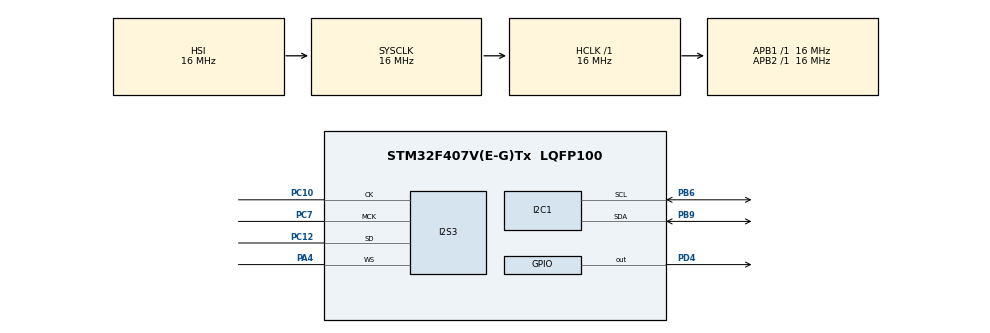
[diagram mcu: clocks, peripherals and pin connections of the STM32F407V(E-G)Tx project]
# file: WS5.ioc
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Dma.Request0=SPI3_TX
Dma.SPI3_TX.0.Direction=DMA_MEMORY_TO_PERIPH
Dma.SPI3_TX.0.FIFOMode=DMA_FIFOMODE_ENABLE
Dma.SPI3_TX.0.FIFOThreshold=DMA_FIFO_THRESHOLD_FULL
Dma.SPI3_TX.0.Instance=DMA1_Stream5
Dma.SPI3_TX.0.MemBurst=DMA_MBURST_SINGLE
Dma.SPI3_TX.0.MemDataAlignment=DMA_MDATAALIGN_HALFWORD
Dma.SPI3_TX.0.MemInc=DMA_MINC_ENABLE
Dma.SPI3_TX.0.Mode=DMA_CIRCULAR
Dma.SPI3_TX.0.PeriphBurst=DMA_PBURST_SINGLE
Dma.SPI3_TX.0.PeriphDataAlignment=DMA_PDATAALIGN_HALFWORD
Dma.SPI3_TX.0.PeriphInc=DMA_PINC_DISABLE
Dma.SPI3_TX.0.Priority=DMA_PRIORITY_LOW
I2S3.AudioFreq=I2S_AUDIOFREQ_48K
I2S3.ErrorAudioFreq=-2.34 %
I2S3.FullDuplexMode=I2S_FULLDUPLEXMODE_DISABLE
I2S3.Instance=SPI$Index
I2S3.RealAudioFreq=46.875 KHz
I2S3.VirtualMode=I2S_MODE_MASTER
Mcu.Family=STM32F4
Mcu.Name=STM32F407V(E-G)Tx
Mcu.Package=LQFP100
NVIC.DMA1_Stream5_IRQn=true\:0\:0\:false\:false\:true\:false\:true\:true
NVIC.PriorityGroup=NVIC_PRIORITYGROUP_4
PA4.Mode=Half_Duplex_Master
PA4.Signal=I2S3_WS
PB6.Mode=I2C
PB6.Signal=I2C1_SCL
PB9.Mode=I2C
PB9.Signal=I2C1_SDA
PC10.Mode=Half_Duplex_Master
PC10.Signal=I2S3_CK
PC12.Mode=Half_Duplex_Master
PC12.Signal=I2S3_SD
PC7.Mode=Master_Clock_Activated
PC7.Signal=I2S3_MCK
PD4.Signal=GPIO_Output
ProjectManager.HeapSize=0x200
ProjectManager.StackSize=0x400
ProjectManager.TargetToolchain=STM32CubeIDE
RCC.AHBFreq_Value=16000000
RCC.APB1Freq_Value=16000000
RCC.APB2Freq_Value=16000000
RCC.CortexFreq_Value=16000000
RCC.HSE_VALUE=25000000
RCC.HSI_VALUE=16000000
RCC.LSE_VALUE=32768
RCC.SYSCLKFreq_VALUE=16000000
RCC.VCOOutputFreq_Value=192000000
board=custom

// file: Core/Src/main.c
/* USER CODE BEGIN Header */
/**
  ******************************************************************************
  * @file           : main.c
  * @brief          : Main program body
  ******************************************************************************
  * @attention
  *
  * Copyright (c) 2024 STMicroelectronics.
  * All rights reserved.
  *
  * This software is licensed under terms that can be found in the LICENSE file
  * in the root directory of this software component.
  * If no LICENSE file comes with this software, it is provided AS-IS.
  *
  ******************************************************************************
  */
/* USER CODE END Header */
#include "main.h"

/* USER CODE BEGIN PTD */

typedef enum
{
    C4,
    D4,
    E4,
    F4,
    G4,
    A4,
    B4,
    C5,
    D5,
    E5,
    F5,
    G5,
    E3,
    G3,
    A3,
    B3,
    F3,
    D3,
    MAX_VALUE
} soundToneType;

/* USER CODE END PTD */

/* USER CODE BEGIN PD */

#define CS43L22_I2C_ADDRESS		0x94
#define I2C_TIMEOUT				10

/* USER CODE END PD */

I2C_HandleTypeDef hi2c1;

I2S_HandleTypeDef hi2s3;
DMA_HandleTypeDef hdma_spi3_tx;

/* USER CODE BEGIN PV */

int16_t dataI2S[100] = {0};

/* USER CODE END PV */

void SystemClock_Config(void);
static void MX_GPIO_Init(void);
static void MX_DMA_Init(void);
static void MX_I2C1_Init(void);
static void MX_I2S3_Init(void);

/* USER CODE BEGIN 0 */

void CS43L22_Init(void)
{
	// Enable chip
	HAL_GPIO_WritePin(GPIOD, GPIO_PIN_4, GPIO_PIN_SET);

	//
	// Initialization
	//
	uint8_t TxBuffer[2];

	TxBuffer[0] = 0x0D;
	TxBuffer[1] = 0x01;
	HAL_I2C_Master_Transmit(&hi2c1, CS43L22_I2C_ADDRESS, (uint8_t*) &TxBuffer, 2, I2C_TIMEOUT);

	TxBuffer[0] = 0x00;
	TxBuffer[1] = 0x99;
	HAL_I2C_Master_Transmit(&hi2c1, CS43L22_I2C_ADDRESS, (uint8_t*) &TxBuffer, 2, I2C_TIMEOUT);

	TxBuffer[0] = 0x47;
	TxBuffer[1] = 0x80;
	HAL_I2C_Master_Transmit(&hi2c1, CS43L22_I2C_ADDRESS, (uint8_t*) &TxBuffer, 2, I2C_TIMEOUT);

	TxBuffer[0] = 0x32;
	TxBuffer[1] = 0xFF;
	HAL_I2C_Master_Transmit(&hi2c1, CS43L22_I2C_ADDRESS, (uint8_t*) &TxBuffer, 2, I2C_TIMEOUT);

	TxBuffer[0] = 0x32;
	TxBuffer[1] = 0x7F;
	HAL_I2C_Master_Transmit(&hi2c1, CS43L22_I2C_ADDRESS, (uint8_t*) &TxBuffer, 2, I2C_TIMEOUT);

	TxBuffer[0] = 0x00;
	TxBuffer[1] = 0x00;
	HAL_I2C_Master_Transmit(&hi2c1, CS43L22_I2C_ADDRESS, (uint8_t*) &TxBuffer, 2, I2C_TIMEOUT);

	TxBuffer[0] = 0x04;
	TxBuffer[1] = 0xAF;
	HAL_I2C_Master_Transmit(&hi2c1, CS43L22_I2C_ADDRESS, (uint8_t*) &TxBuffer, 2, I2C_TIMEOUT);

	TxBuffer[0] = 0x0D;
	TxBuffer[1] = 0x70;
	HAL_I2C_Master_Transmit(&hi2c1, CS43L22_I2C_ADDRESS, (uint8_t*) &TxBuffer, 2, I2C_TIMEOUT);

	TxBuffer[0] = 0x05;
	TxBuffer[1] = 0x81;
	HAL_I2C_Master_Transmit(&hi2c1, CS43L22_I2C_ADDRESS, (uint8_t*) &TxBuffer, 2, I2C_TIMEOUT);

	TxBuffer[0] = 0x06;
	TxBuffer[1] = 0x07;
	HAL_I2C_Master_Transmit(&hi2c1, CS43L22_I2C_ADDRESS, (uint8_t*) &TxBuffer, 2, I2C_TIMEOUT);

	TxBuffer[0] = 0x0A;
	TxBuffer[1] = 0x00;
	HAL_I2C_Master_Transmit(&hi2c1, CS43L22_I2C_ADDRESS, (uint8_t*) &TxBuffer, 2, I2C_TIMEOUT);

	TxBuffer[0] = 0x27;
	TxBuffer[1] = 0x00;
	HAL_I2C_Master_Transmit(&hi2c1, CS43L22_I2C_ADDRESS, (uint8_t*) &TxBuffer, 2, I2C_TIMEOUT);

	TxBuffer[0] = 0x1A;
	TxBuffer[1] = 0x0A;
	HAL_I2C_Master_Transmit(&hi2c1, CS43L22_I2C_ADDRESS, (uint8_t*) &TxBuffer, 2, I2C_TIMEOUT);

	TxBuffer[0] = 0x1B;
	TxBuffer[1] = 0x0A;
	HAL_I2C_Master_Transmit(&hi2c1, CS43L22_I2C_ADDRESS, (uint8_t*) &TxBuffer, 2, I2C_TIMEOUT);

	TxBuffer[0] = 0x1F;
	TxBuffer[1] = 0x0F;
	HAL_I2C_Master_Transmit(&hi2c1, CS43L22_I2C_ADDRESS, (uint8_t*) &TxBuffer, 2, I2C_TIMEOUT);

	TxBuffer[0] = 0x02;
	TxBuffer[1] = 0x9E;
	HAL_I2C_Master_Transmit(&hi2c1, CS43L22_I2C_ADDRESS, (uint8_t*) &TxBuffer, 2, I2C_TIMEOUT);
}

void CS43L22_Beep(soundToneType pitch, uint32_t duration_ms)
{
    uint8_t TxBuffer[2];

    // Set volume and off time
    TxBuffer[0] = 0x1D;     // Register address
    TxBuffer[1] = 0x00;     // Value (volume and off time)
    HAL_I2C_Master_Transmit(&hi2c1, CS43L22_I2C_ADDRESS, (uint8_t*) &TxBuffer, 2, I2C_TIMEOUT);

    // Set sound frequency
    TxBuffer[0] = 0x1C;     // Register address
    switch (pitch)
    {
        case C4:
            TxBuffer[1] = 0x00;     // Value (frequency for C4)
            break;
        case D4:
            TxBuffer[1] = 0x01;     // Value (frequency for D4)
            break;
        case E4:
            TxBuffer[1] = 0x02;     // Value (frequency for E4)
            break;
        case F4:
            TxBuffer[1] = 0x03;     // Value (frequency for F4)
            break;
        case G4:
            TxBuffer[1] = 0x04;     // Value (frequency for G4)
            break;
        case A4:
            TxBuffer[1] = 0x05;     // Value (frequency for A4)
            break;
        case B4:
            TxBuffer[1] = 0x06;     // Value (frequency for B4)
            break;
        case C5:
            TxBuffer[1] = 0x07;     // Value (frequency for C5)
            break;
        case D5:
            TxBuffer[1] = 0x08;     // Value (frequency for D5)
            break;
        case E5:
            TxBuffer[1] = 0x09;     // Value (frequency for E5)
            break;
        case F5:
            TxBuffer[1] = 0x0A;     // Value (frequency for F5)
            break;
        case G5:
            TxBuffer[1] = 0x0B;     // Value (frequency for G5)
            break;
        case E3:
            TxBuffer[1] = 0x0C;     // Value (frequency for E3)
            break;
        case G3:
            TxBuffer[1] = 0x0D;     // Value (frequency for G3)
            break;
        case A3:
            TxBuffer[1] = 0x0E;     // Value (frequency for A3)
            break;
        case B3:
            TxBuffer[1] = 0x0F;     // Value (frequency for B3)
            break;
        case F3:
            TxBuffer[1] = 0x10;     // Value (frequency for F3)
            break;
        case D3:
            TxBuffer[1] = 0x11;     // Value (frequency for D3)
            break;
        case MAX_VALUE:
        default:
            TxBuffer[1] = 0x00;     // Default to C4
            break;
    }
    HAL_I2C_Master_Transmit(&hi2c1, CS43L22_I2C_ADDRESS, (uint8_t*) &TxBuffer, 2, I2C_TIMEOUT);

    // Enable continuous mode (SOUND STARTED)
    TxBuffer[0] = 0x1E;     // Register address
    TxBuffer[1] = 0xC0;     // Value (beep and tone configuration)
    HAL_I2C_Master_Transmit(&hi2c1, CS43L22_I2C_ADDRESS, (uint8_t*) &TxBuffer, 2, I2C_TIMEOUT);

    // Playing...
    HAL_Delay(duration_ms);

    // Disable continuous mode (SOUND STOPPED)
    TxBuffer[0] = 0x1E;     // Register address
    TxBuffer[1] = 0x00;     // Value (beep and tone configuration)
    HAL_I2C_Master_Transmit(&hi2c1, CS43L22_I2C_ADDRESS, (uint8_t*) &TxBuffer, 2, I2C_TIMEOUT);
}

/* USER CODE END 0 */

int main(void)
{

  /* MCU Configuration--------------------------------------------------------*/

  /* Reset of all peripherals, Initializes the Flash interface and the Systick. */
  HAL_Init();

  /* Configure the system clock */
  SystemClock_Config();

  /* Initialize all configured peripherals */
  MX_GPIO_Init();
  MX_DMA_Init();
  MX_I2C1_Init();
  MX_I2S3_Init();
  /* USER CODE BEGIN 2 */

  // Init DAC
  CS43L22_Init();

  // Transmit empty data
  HAL_I2S_Transmit_DMA(&hi2s3, (uint16_t *)dataI2S, 100);
  int loopCount = 0;
  /* USER CODE END 2 */

  /* Infinite loop */
  /* USER CODE BEGIN WHILE */
  while (1)
  {
	    if (loopCount < 3) {
	      CS43L22_Beep(E4, 200);
	        HAL_GPIO_WritePin(GPIOD, GPIO_PIN_12, GPIO_PIN_SET);
	        HAL_GPIO_WritePin(GPIOD, GPIO_PIN_13, GPIO_PIN_RESET);
	        HAL_GPIO_WritePin(GPIOD, GPIO_PIN_14, GPIO_PIN_RESET);
	        HAL_GPIO_WritePin(GPIOD, GPIO_PIN_15, GPIO_PIN_RESET);
	      HAL_Delay(100);

	      CS43L22_Beep(E4, 200);
	        HAL_GPIO_WritePin(GPIOD, GPIO_PIN_12, GPIO_PIN_RESET);
	        HAL_GPIO_WritePin(GPIOD, GPIO_PIN_13, GPIO_PIN_SET);
	        HAL_GPIO_WritePin(GPIOD, GPIO_PIN_14, GPIO_PIN_RESET);
	        HAL_GPIO_WritePin(GPIOD, GPIO_PIN_15, GPIO_PIN_RESET);
	      HAL_Delay(100);

	      CS43L22_Beep(E4, 200);
	        HAL_GPIO_WritePin(GPIOD, GPIO_PIN_12, GPIO_PIN_RESET);
	        HAL_GPIO_WritePin(GPIOD, GPIO_PIN_13, GPIO_PIN_RESET);
	        HAL_GPIO_WritePin(GPIOD, GPIO_PIN_14, GPIO_PIN_SET);
	        HAL_GPIO_WritePin(GPIOD, GPIO_PIN_15, GPIO_PIN_RESET);
	      HAL_Delay(100);

	      CS43L22_Beep(C4, 200);
	        HAL_GPIO_WritePin(GPIOD, GPIO_PIN_12, GPIO_PIN_RESET);
	        HAL_GPIO_WritePin(GPIOD, GPIO_PIN_13, GPIO_PIN_RESET);
	        HAL_GPIO_WritePin(GPIOD, GPIO_PIN_14, GPIO_PIN_RESET);
	        HAL_GPIO_WritePin(GPIOD, GPIO_PIN_15, GPIO_PIN_SET);
	      HAL_Delay(100);

	      CS43L22_Beep(E4, 200);
	        HAL_GPIO_WritePin(GPIOD, GPIO_PIN_12, GPIO_PIN_SET);
	        HAL_GPIO_WritePin(GPIOD, GPIO_PIN_13, GPIO_PIN_RESET);
	        HAL_GPIO_WritePin(GPIOD, GPIO_PIN_14, GPIO_PIN_RESET);
	        HAL_GPIO_WritePin(GPIOD, GPIO_PIN_15, GPIO_PIN_RESET);
	      HAL_Delay(100);

	      CS43L22_Beep(G4, 200);
	        HAL_GPIO_WritePin(GPIOD, GPIO_PIN_12, GPIO_PIN_SET);
	        HAL_GPIO_WritePin(GPIOD, GPIO_PIN_13, GPIO_PIN_SET);
	        HAL_GPIO_WritePin(GPIOD, GPIO_PIN_14, GPIO_PIN_SET);
	        HAL_GPIO_WritePin(GPIOD, GPIO_PIN_15, GPIO_PIN_SET);
	      HAL_Delay(300);

	      CS43L22_Beep(G3, 200);
	        HAL_GPIO_WritePin(GPIOD, GPIO_PIN_12, GPIO_PIN_SET);
	        HAL_GPIO_WritePin(GPIOD, GPIO_PIN_13, GPIO_PIN_SET);
	        HAL_GPIO_WritePin(GPIOD, GPIO_PIN_14, GPIO_PIN_SET);
	        HAL_GPIO_WritePin(GPIOD, GPIO_PIN_15, GPIO_PIN_SET);
	      HAL_Delay(300);

	      // Phrase 2
	      CS43L22_Beep(C4, 200);
	        HAL_GPIO_WritePin(GPIOD, GPIO_PIN_12, GPIO_PIN_SET);
	        HAL_GPIO_WritePin(GPIOD, GPIO_PIN_13, GPIO_PIN_RESET);
	        HAL_GPIO_WritePin(GPIOD, GPIO_PIN_14, GPIO_PIN_RESET);
	        HAL_GPIO_WritePin(GPIOD, GPIO_PIN_15, GPIO_PIN_RESET);
	      HAL_Delay(100);

	      CS43L22_Beep(G3, 200);
	        HAL_GPIO_WritePin(GPIOD, GPIO_PIN_12, GPIO_PIN_SET);
	        HAL_GPIO_WritePin(GPIOD, GPIO_PIN_13, GPIO_PIN_SET);
	        HAL_GPIO_WritePin(GPIOD, GPIO_PIN_14, GPIO_PIN_SET);
	        HAL_GPIO_WritePin(GPIOD, GPIO_PIN_15, GPIO_PIN_SET);
	      HAL_Delay(300);

	      CS43L22_Beep(E3, 200);
	        HAL_GPIO_WritePin(GPIOD, GPIO_PIN_12, GPIO_PIN_SET);
	        HAL_GPIO_WritePin(GPIOD, GPIO_PIN_13, GPIO_PIN_SET);
	        HAL_GPIO_WritePin(GPIOD, GPIO_PIN_14, GPIO_PIN_SET);
	        HAL_GPIO_WritePin(GPIOD, GPIO_PIN_15, GPIO_PIN_SET);
	      HAL_Delay(300);

	      CS43L22_Beep(A3, 200);
	        HAL_GPIO_WritePin(GPIOD, GPIO_PIN_12, GPIO_PIN_RESET);
	        HAL_GPIO_WritePin(GPIOD, GPIO_PIN_13, GPIO_PIN_SET);
	        HAL_GPIO_WritePin(GPIOD, GPIO_PIN_14, GPIO_PIN_RESET);
	        HAL_GPIO_WritePin(GPIOD, GPIO_PIN_15, GPIO_PIN_RESET);
	      HAL_Delay(100);

	      CS43L22_Beep(B3, 200);
	        HAL_GPIO_WritePin(GPIOD, GPIO_PIN_12, GPIO_PIN_RESET);
	        HAL_GPIO_WritePin(GPIOD, GPIO_PIN_13, GPIO_PIN_RESET);
	        HAL_GPIO_WritePin(GPIOD, GPIO_PIN_14, GPIO_PIN_SET);
	        HAL_GPIO_WritePin(GPIOD, GPIO_PIN_15, GPIO_PIN_RESET);
	      HAL_Delay(100);

	      CS43L22_Beep(B3, 200);
	        HAL_GPIO_WritePin(GPIOD, GPIO_PIN_12, GPIO_PIN_RESET);
	        HAL_GPIO_WritePin(GPIOD, GPIO_PIN_13, GPIO_PIN_RESET);
	        HAL_GPIO_WritePin(GPIOD, GPIO_PIN_14, GPIO_PIN_RESET);
	        HAL_GPIO_WritePin(GPIOD, GPIO_PIN_15, GPIO_PIN_SET);
	      HAL_Delay(100);

	      CS43L22_Beep(A3, 200);
	        HAL_GPIO_WritePin(GPIOD, GPIO_PIN_12, GPIO_PIN_RESET);
	        HAL_GPIO_WritePin(GPIOD, GPIO_PIN_13, GPIO_PIN_SET);
	        HAL_GPIO_WritePin(GPIOD, GPIO_PIN_14, GPIO_PIN_SET);
	        HAL_GPIO_WritePin(GPIOD, GPIO_PIN_15, GPIO_PIN_SET);
	      HAL_Delay(100);
          loopCount++;
      }
      else
      {
          break;
      }
  }

  while (1)
  {
     //Не дякуйте!
  }

}

void SystemClock_Config(void)
{
  RCC_OscInitTypeDef RCC_OscInitStruct = {0};
  RCC_ClkInitTypeDef RCC_ClkInitStruct = {0};

  /** Macro to configure the PLL multiplication factor
  */
  __HAL_RCC_PLL_PLLM_CONFIG(16);

  /** Macro to configure the PLL clock source
  */
  __HAL_RCC_PLL_PLLSOURCE_CONFIG(RCC_PLLSOURCE_HSI);

  /** Configure the main internal regulator output voltage
  */
  __HAL_RCC_PWR_CLK_ENABLE();
  __HAL_PWR_VOLTAGESCALING_CONFIG(PWR_REGULATOR_VOLTAGE_SCALE1);

  /** Initializes the RCC Oscillators according to the specified parameters
  * in the RCC_OscInitTypeDef structure.
  */
  RCC_OscInitStruct.OscillatorType = RCC_OSCILLATORTYPE_HSI;
  RCC_OscInitStruct.HSIState = RCC_HSI_ON;
  RCC_OscInitStruct.HSICalibrationValue = RCC_HSICALIBRATION_DEFAULT;
  RCC_OscInitStruct.PLL.PLLState = RCC_PLL_NONE;
  RCC_OscInitStruct.PLL.PLLSource = RCC_PLLSOURCE_HSI;
  if (HAL_RCC_OscConfig(&RCC_OscInitStruct) != HAL_OK)
  {
    Error_Handler();
  }

  /** Initializes the CPU, AHB and APB buses clocks
  */
  RCC_ClkInitStruct.ClockType = RCC_CLOCKTYPE_HCLK|RCC_CLOCKTYPE_SYSCLK
                              |RCC_CLOCKTYPE_PCLK1|RCC_CLOCKTYPE_PCLK2;
  RCC_ClkInitStruct.SYSCLKSource = RCC_SYSCLKSOURCE_HSI;
  RCC_ClkInitStruct.AHBCLKDivider = RCC_SYSCLK_DIV1;
  RCC_ClkInitStruct.APB1CLKDivider = RCC_HCLK_DIV1;
  RCC_ClkInitStruct.APB2CLKDivider = RCC_HCLK_DIV1;

  if (HAL_RCC_ClockConfig(&RCC_ClkInitStruct, FLASH_LATENCY_0) != HAL_OK)
  {
    Error_Handler();
  }
}

static void MX_I2C1_Init(void)
{

  hi2c1.Instance = I2C1;
  hi2c1.Init.ClockSpeed = 100000;
  hi2c1.Init.DutyCycle = I2C_DUTYCYCLE_2;
  hi2c1.Init.OwnAddress1 = 0;
  hi2c1.Init.AddressingMode = I2C_ADDRESSINGMODE_7BIT;
  hi2c1.Init.DualAddressMode = I2C_DUALADDRESS_DISABLE;
  hi2c1.Init.OwnAddress2 = 0;
  hi2c1.Init.GeneralCallMode = I2C_GENERALCALL_DISABLE;
  hi2c1.Init.NoStretchMode = I2C_NOSTRETCH_DISABLE;
  if (HAL_I2C_Init(&hi2c1) != HAL_OK)
  {
    Error_Handler();
  }

}

static void MX_I2S3_Init(void)
{

  hi2s3.Instance = SPI3;
  hi2s3.Init.Mode = I2S_MODE_MASTER_TX;
  hi2s3.Init.Standard = I2S_STANDARD_PHILIPS;
  hi2s3.Init.DataFormat = I2S_DATAFORMAT_16B;
  hi2s3.Init.MCLKOutput = I2S_MCLKOUTPUT_ENABLE;
  hi2s3.Init.AudioFreq = I2S_AUDIOFREQ_48K;
  hi2s3.Init.CPOL = I2S_CPOL_LOW;
  hi2s3.Init.ClockSource = I2S_CLOCK_PLL;
  hi2s3.Init.FullDuplexMode = I2S_FULLDUPLEXMODE_DISABLE;
  if (HAL_I2S_Init(&hi2s3) != HAL_OK)
  {
    Error_Handler();
  }

}

static void MX_DMA_Init(void)
{

  /* DMA controller clock enable */
  __HAL_RCC_DMA1_CLK_ENABLE();

  /* DMA interrupt init */
  /* DMA1_Stream5_IRQn interrupt configuration */
  HAL_NVIC_SetPriority(DMA1_Stream5_IRQn, 0, 0);
  HAL_NVIC_EnableIRQ(DMA1_Stream5_IRQn);

}

static void MX_GPIO_Init(void)
{
  GPIO_InitTypeDef GPIO_InitStruct = {0};

  /* GPIO Ports Clock Enable */
  __HAL_RCC_GPIOA_CLK_ENABLE();
  __HAL_RCC_GPIOD_CLK_ENABLE();
  __HAL_RCC_GPIOC_CLK_ENABLE();
  __HAL_RCC_GPIOB_CLK_ENABLE();

  /*Configure GPIO pin Output Level */
  HAL_GPIO_WritePin(GPIOD, GPIO_PIN_12|GPIO_PIN_13|GPIO_PIN_14|GPIO_PIN_15
                          |GPIO_PIN_4, GPIO_PIN_RESET);

  /*Configure GPIO pins : PD12 PD13 PD14 PD15
                           PD4 */
  GPIO_InitStruct.Pin = GPIO_PIN_12|GPIO_PIN_13|GPIO_PIN_14|GPIO_PIN_15
                          |GPIO_PIN_4;
  GPIO_InitStruct.Mode = GPIO_MODE_OUTPUT_PP;
  GPIO_InitStruct.Pull = GPIO_NOPULL;
  GPIO_InitStruct.Speed = GPIO_SPEED_FREQ_LOW;
  HAL_GPIO_Init(GPIOD, &GPIO_InitStruct);

}

void Error_Handler(void)
{
  __disable_irq();
  while (1)
  {
  }
}
